VERSION 5.8 ;
BUSBITCHARS "[]" ;
DIVIDERCHAR "/" ;
UNITS
    DATABASE MICRONS 1000 ;
END UNITS

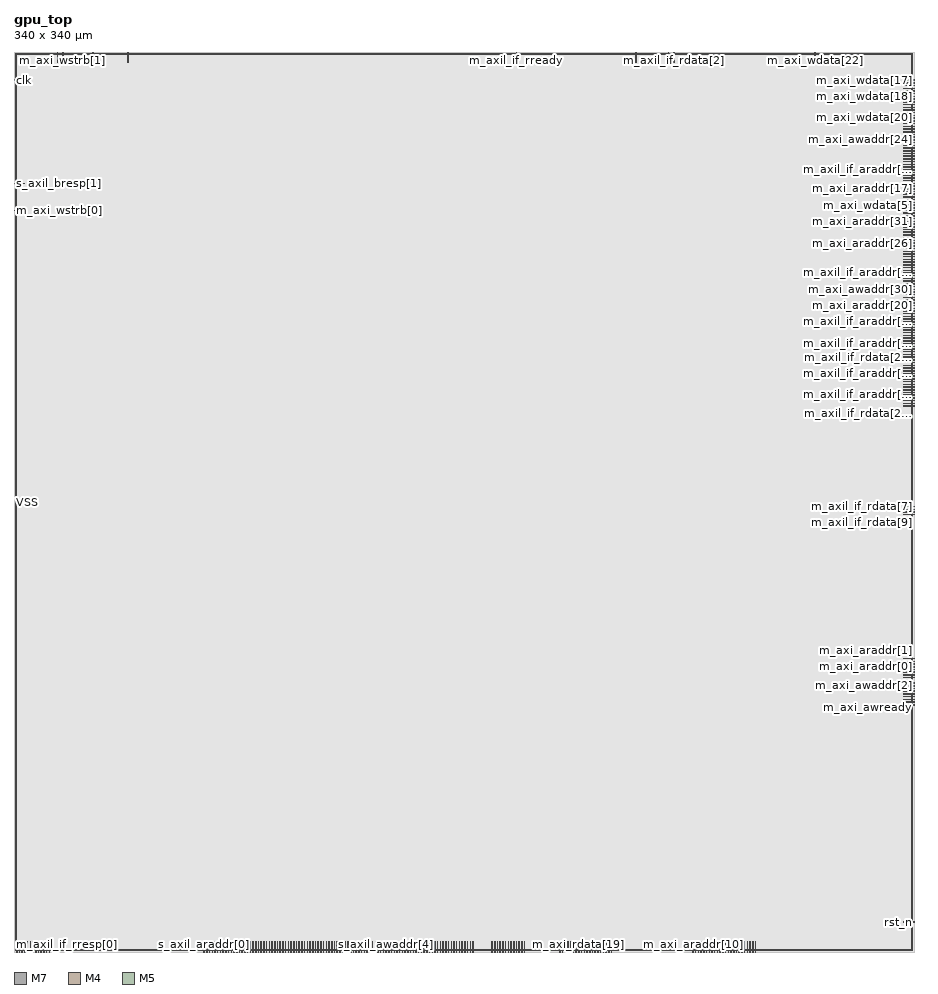
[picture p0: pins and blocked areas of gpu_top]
MACRO gpu_top
  FOREIGN gpu_top 0 0 ;
  CLASS BLOCK ;
  SIZE 340 BY 340 ;
  PIN VDD
    USE POWER ;
    DIRECTION INOUT ;
    PORT
      LAYER M7 ;
        RECT 0.500 0.500 339.500 0.660 ;
        RECT 0.500 339.340 339.500 339.500 ;
        RECT 0.500 0.500 0.660 339.500 ;
        RECT 339.340 0.500 339.500 339.500 ;
    END
  END VDD
  PIN VSS
    USE GROUND ;
    DIRECTION INOUT ;
    PORT
      LAYER M7 ;
        RECT 0.500 0.820 339.500 0.980 ;
        RECT 0.500 339.020 339.500 339.180 ;
        RECT 0.500 0.820 0.980 339.180 ;
        RECT 339.020 0.500 339.180 339.500 ;
    END
  END VSS
  PIN clk
    DIRECTION INPUT ;
    USE SIGNAL ;
    PORT
      LAYER M4 ;
        RECT  0 329.268 4 329.46 ;
    END
  END clk
  PIN gpu_irq_o
    DIRECTION OUTPUT ;
    USE SIGNAL ;
    PORT
      LAYER M5 ;
        RECT  116.886 0 117.078 4 ;
    END
  END gpu_irq_o
  PIN m_axi_araddr[0]
    DIRECTION OUTPUT ;
    USE SIGNAL ;
    PORT
      LAYER M4 ;
        RECT  336 107.652 340 107.844 ;
    END
  END m_axi_araddr[0]
  PIN m_axi_araddr[10]
    DIRECTION OUTPUT ;
    USE SIGNAL ;
    PORT
      LAYER M5 ;
        RECT  256.422 0 256.614 4 ;
    END
  END m_axi_araddr[10]
  PIN m_axi_araddr[11]
    DIRECTION OUTPUT ;
    USE SIGNAL ;
    PORT
      LAYER M5 ;
        RECT  258.474 0 258.666 4 ;
    END
  END m_axi_araddr[11]
  PIN m_axi_araddr[12]
    DIRECTION OUTPUT ;
    USE SIGNAL ;
    PORT
      LAYER M5 ;
        RECT  266.682 0 266.874 4 ;
    END
  END m_axi_araddr[12]
  PIN m_axi_araddr[13]
    DIRECTION OUTPUT ;
    USE SIGNAL ;
    PORT
      LAYER M5 ;
        RECT  260.526 0 260.718 4 ;
    END
  END m_axi_araddr[13]
  PIN m_axi_araddr[14]
    DIRECTION OUTPUT ;
    USE SIGNAL ;
    PORT
      LAYER M5 ;
        RECT  280.02 0 280.212 4 ;
    END
  END m_axi_araddr[14]
  PIN m_axi_araddr[15]
    DIRECTION OUTPUT ;
    USE SIGNAL ;
    PORT
      LAYER M5 ;
        RECT  269.76 0 269.952 4 ;
    END
  END m_axi_araddr[15]
  PIN m_axi_araddr[16]
    DIRECTION OUTPUT ;
    USE SIGNAL ;
    PORT
      LAYER M4 ;
        RECT  336 314.904 340 315.096 ;
    END
  END m_axi_araddr[16]
  PIN m_axi_araddr[17]
    DIRECTION OUTPUT ;
    USE SIGNAL ;
    PORT
      LAYER M4 ;
        RECT  336 291.306 340 291.498 ;
    END
  END m_axi_araddr[17]
  PIN m_axi_araddr[18]
    DIRECTION OUTPUT ;
    USE SIGNAL ;
    PORT
      LAYER M4 ;
        RECT  336 273.864 340 274.056 ;
    END
  END m_axi_araddr[18]
  PIN m_axi_araddr[19]
    DIRECTION OUTPUT ;
    USE SIGNAL ;
    PORT
      LAYER M4 ;
        RECT  336 274.89 340 275.082 ;
    END
  END m_axi_araddr[19]
  PIN m_axi_araddr[1]
    DIRECTION OUTPUT ;
    USE SIGNAL ;
    PORT
      LAYER M4 ;
        RECT  336 110.73 340 110.922 ;
    END
  END m_axi_araddr[1]
  PIN m_axi_araddr[20]
    DIRECTION OUTPUT ;
    USE SIGNAL ;
    PORT
      LAYER M4 ;
        RECT  336 244.11 340 244.302 ;
    END
  END m_axi_araddr[20]
  PIN m_axi_araddr[21]
    DIRECTION OUTPUT ;
    USE SIGNAL ;
    PORT
      LAYER M4 ;
        RECT  336 290.28 340 290.472 ;
    END
  END m_axi_araddr[21]
  PIN m_axi_araddr[22]
    DIRECTION OUTPUT ;
    USE SIGNAL ;
    PORT
      LAYER M4 ;
        RECT  336 258.474 340 258.666 ;
    END
  END m_axi_araddr[22]
  PIN m_axi_araddr[23]
    DIRECTION OUTPUT ;
    USE SIGNAL ;
    PORT
      LAYER M4 ;
        RECT  336 312.852 340 313.044 ;
    END
  END m_axi_araddr[23]
  PIN m_axi_araddr[24]
    DIRECTION OUTPUT ;
    USE SIGNAL ;
    PORT
      LAYER M4 ;
        RECT  336 251.292 340 251.484 ;
    END
  END m_axi_araddr[24]
  PIN m_axi_araddr[25]
    DIRECTION OUTPUT ;
    USE SIGNAL ;
    PORT
      LAYER M4 ;
        RECT  336 263.604 340 263.796 ;
    END
  END m_axi_araddr[25]
  PIN m_axi_araddr[26]
    DIRECTION OUTPUT ;
    USE SIGNAL ;
    PORT
      LAYER M4 ;
        RECT  336 267.708 340 267.9 ;
    END
  END m_axi_araddr[26]
  PIN m_axi_araddr[27]
    DIRECTION OUTPUT ;
    USE SIGNAL ;
    PORT
      LAYER M4 ;
        RECT  336 303.618 340 303.81 ;
    END
  END m_axi_araddr[27]
  PIN m_axi_araddr[28]
    DIRECTION OUTPUT ;
    USE SIGNAL ;
    PORT
      LAYER M4 ;
        RECT  336 277.968 340 278.16 ;
    END
  END m_axi_araddr[28]
  PIN m_axi_araddr[29]
    DIRECTION OUTPUT ;
    USE SIGNAL ;
    PORT
      LAYER M4 ;
        RECT  336 245.136 340 245.328 ;
    END
  END m_axi_araddr[29]
  PIN m_axi_araddr[2]
    DIRECTION OUTPUT ;
    USE SIGNAL ;
    PORT
      LAYER M4 ;
        RECT  336 104.574 340 104.766 ;
    END
  END m_axi_araddr[2]
  PIN m_axi_araddr[30]
    DIRECTION OUTPUT ;
    USE SIGNAL ;
    PORT
      LAYER M4 ;
        RECT  336 310.8 340 310.992 ;
    END
  END m_axi_araddr[30]
  PIN m_axi_araddr[31]
    DIRECTION OUTPUT ;
    USE SIGNAL ;
    PORT
      LAYER M4 ;
        RECT  336 272.838 340 273.03 ;
    END
  END m_axi_araddr[31]
  PIN m_axi_araddr[3]
    DIRECTION OUTPUT ;
    USE SIGNAL ;
    PORT
      LAYER M4 ;
        RECT  336 105.6 340 105.792 ;
    END
  END m_axi_araddr[3]
  PIN m_axi_araddr[4]
    DIRECTION OUTPUT ;
    USE SIGNAL ;
    PORT
      LAYER M5 ;
        RECT  267.708 0 267.9 4 ;
    END
  END m_axi_araddr[4]
  PIN m_axi_araddr[5]
    DIRECTION OUTPUT ;
    USE SIGNAL ;
    PORT
      LAYER M5 ;
        RECT  278.994 0 279.186 4 ;
    END
  END m_axi_araddr[5]
  PIN m_axi_araddr[6]
    DIRECTION OUTPUT ;
    USE SIGNAL ;
    PORT
      LAYER M5 ;
        RECT  263.604 0 263.796 4 ;
    END
  END m_axi_araddr[6]
  PIN m_axi_araddr[7]
    DIRECTION OUTPUT ;
    USE SIGNAL ;
    PORT
      LAYER M5 ;
        RECT  257.448 0 257.64 4 ;
    END
  END m_axi_araddr[7]
  PIN m_axi_araddr[8]
    DIRECTION OUTPUT ;
    USE SIGNAL ;
    PORT
      LAYER M5 ;
        RECT  272.838 0 273.03 4 ;
    END
  END m_axi_araddr[8]
  PIN m_axi_araddr[9]
    DIRECTION OUTPUT ;
    USE SIGNAL ;
    PORT
      LAYER M5 ;
        RECT  277.968 0 278.16 4 ;
    END
  END m_axi_araddr[9]
  PIN m_axi_arready
    DIRECTION INPUT ;
    USE SIGNAL ;
    PORT
      LAYER M4 ;
        RECT  336 93.288 340 93.48 ;
    END
  END m_axi_arready
  PIN m_axi_arvalid
    DIRECTION OUTPUT ;
    USE SIGNAL ;
    PORT
      LAYER M4 ;
        RECT  336 94.314 340 94.506 ;
    END
  END m_axi_arvalid
  PIN m_axi_awaddr[0]
    DIRECTION OUTPUT ;
    USE SIGNAL ;
    PORT
      LAYER M4 ;
        RECT  336 108.678 340 108.87 ;
    END
  END m_axi_awaddr[0]
  PIN m_axi_awaddr[10]
    DIRECTION OUTPUT ;
    USE SIGNAL ;
    PORT
      LAYER M5 ;
        RECT  265.656 0 265.848 4 ;
    END
  END m_axi_awaddr[10]
  PIN m_axi_awaddr[11]
    DIRECTION OUTPUT ;
    USE SIGNAL ;
    PORT
      LAYER M5 ;
        RECT  268.734 0 268.926 4 ;
    END
  END m_axi_awaddr[11]
  PIN m_axi_awaddr[12]
    DIRECTION OUTPUT ;
    USE SIGNAL ;
    PORT
      LAYER M5 ;
        RECT  264.63 0 264.822 4 ;
    END
  END m_axi_awaddr[12]
  PIN m_axi_awaddr[13]
    DIRECTION OUTPUT ;
    USE SIGNAL ;
    PORT
      LAYER M5 ;
        RECT  259.5 0 259.692 4 ;
    END
  END m_axi_awaddr[13]
  PIN m_axi_awaddr[14]
    DIRECTION OUTPUT ;
    USE SIGNAL ;
    PORT
      LAYER M5 ;
        RECT  270.786 0 270.978 4 ;
    END
  END m_axi_awaddr[14]
  PIN m_axi_awaddr[15]
    DIRECTION OUTPUT ;
    USE SIGNAL ;
    PORT
      LAYER M5 ;
        RECT  275.916 0 276.108 4 ;
    END
  END m_axi_awaddr[15]
  PIN m_axi_awaddr[16]
    DIRECTION OUTPUT ;
    USE SIGNAL ;
    PORT
      LAYER M4 ;
        RECT  336 288.228 340 288.42 ;
    END
  END m_axi_awaddr[16]
  PIN m_axi_awaddr[17]
    DIRECTION OUTPUT ;
    USE SIGNAL ;
    PORT
      LAYER M4 ;
        RECT  336 305.67 340 305.862 ;
    END
  END m_axi_awaddr[17]
  PIN m_axi_awaddr[18]
    DIRECTION OUTPUT ;
    USE SIGNAL ;
    PORT
      LAYER M4 ;
        RECT  336 252.318 340 252.51 ;
    END
  END m_axi_awaddr[18]
  PIN m_axi_awaddr[19]
    DIRECTION OUTPUT ;
    USE SIGNAL ;
    PORT
      LAYER M4 ;
        RECT  336 292.332 340 292.524 ;
    END
  END m_axi_awaddr[19]
  PIN m_axi_awaddr[1]
    DIRECTION OUTPUT ;
    USE SIGNAL ;
    PORT
      LAYER M4 ;
        RECT  336 109.704 340 109.896 ;
    END
  END m_axi_awaddr[1]
  PIN m_axi_awaddr[20]
    DIRECTION OUTPUT ;
    USE SIGNAL ;
    PORT
      LAYER M4 ;
        RECT  336 243.084 340 243.276 ;
    END
  END m_axi_awaddr[20]
  PIN m_axi_awaddr[21]
    DIRECTION OUTPUT ;
    USE SIGNAL ;
    PORT
      LAYER M4 ;
        RECT  336 293.358 340 293.55 ;
    END
  END m_axi_awaddr[21]
  PIN m_axi_awaddr[22]
    DIRECTION OUTPUT ;
    USE SIGNAL ;
    PORT
      LAYER M4 ;
        RECT  336 280.02 340 280.212 ;
    END
  END m_axi_awaddr[22]
  PIN m_axi_awaddr[23]
    DIRECTION OUTPUT ;
    USE SIGNAL ;
    PORT
      LAYER M4 ;
        RECT  336 255.396 340 255.588 ;
    END
  END m_axi_awaddr[23]
  PIN m_axi_awaddr[24]
    DIRECTION OUTPUT ;
    USE SIGNAL ;
    PORT
      LAYER M4 ;
        RECT  336 306.696 340 306.888 ;
    END
  END m_axi_awaddr[24]
  PIN m_axi_awaddr[25]
    DIRECTION OUTPUT ;
    USE SIGNAL ;
    PORT
      LAYER M4 ;
        RECT  336 302.592 340 302.784 ;
    END
  END m_axi_awaddr[25]
  PIN m_axi_awaddr[26]
    DIRECTION OUTPUT ;
    USE SIGNAL ;
    PORT
      LAYER M4 ;
        RECT  336 297.462 340 297.654 ;
    END
  END m_axi_awaddr[26]
  PIN m_axi_awaddr[27]
    DIRECTION OUTPUT ;
    USE SIGNAL ;
    PORT
      LAYER M4 ;
        RECT  336 282.072 340 282.264 ;
    END
  END m_axi_awaddr[27]
  PIN m_axi_awaddr[28]
    DIRECTION OUTPUT ;
    USE SIGNAL ;
    PORT
      LAYER M4 ;
        RECT  336 276.942 340 277.134 ;
    END
  END m_axi_awaddr[28]
  PIN m_axi_awaddr[29]
    DIRECTION OUTPUT ;
    USE SIGNAL ;
    PORT
      LAYER M4 ;
        RECT  336 246.162 340 246.354 ;
    END
  END m_axi_awaddr[29]
  PIN m_axi_awaddr[2]
    DIRECTION OUTPUT ;
    USE SIGNAL ;
    PORT
      LAYER M4 ;
        RECT  336 103.548 340 103.74 ;
    END
  END m_axi_awaddr[2]
  PIN m_axi_awaddr[30]
    DIRECTION OUTPUT ;
    USE SIGNAL ;
    PORT
      LAYER M4 ;
        RECT  336 247.188 340 247.38 ;
    END
  END m_axi_awaddr[30]
  PIN m_axi_awaddr[31]
    DIRECTION OUTPUT ;
    USE SIGNAL ;
    PORT
      LAYER M4 ;
        RECT  336 271.812 340 272.004 ;
    END
  END m_axi_awaddr[31]
  PIN m_axi_awaddr[3]
    DIRECTION OUTPUT ;
    USE SIGNAL ;
    PORT
      LAYER M4 ;
        RECT  336 106.626 340 106.818 ;
    END
  END m_axi_awaddr[3]
  PIN m_axi_awaddr[4]
    DIRECTION OUTPUT ;
    USE SIGNAL ;
    PORT
      LAYER M5 ;
        RECT  262.578 0 262.77 4 ;
    END
  END m_axi_awaddr[4]
  PIN m_axi_awaddr[5]
    DIRECTION OUTPUT ;
    USE SIGNAL ;
    PORT
      LAYER M5 ;
        RECT  276.942 0 277.134 4 ;
    END
  END m_axi_awaddr[5]
  PIN m_axi_awaddr[6]
    DIRECTION OUTPUT ;
    USE SIGNAL ;
    PORT
      LAYER M5 ;
        RECT  261.552 0 261.744 4 ;
    END
  END m_axi_awaddr[6]
  PIN m_axi_awaddr[7]
    DIRECTION OUTPUT ;
    USE SIGNAL ;
    PORT
      LAYER M5 ;
        RECT  274.89 0 275.082 4 ;
    END
  END m_axi_awaddr[7]
  PIN m_axi_awaddr[8]
    DIRECTION OUTPUT ;
    USE SIGNAL ;
    PORT
      LAYER M5 ;
        RECT  273.864 0 274.056 4 ;
    END
  END m_axi_awaddr[8]
  PIN m_axi_awaddr[9]
    DIRECTION OUTPUT ;
    USE SIGNAL ;
    PORT
      LAYER M5 ;
        RECT  271.812 0 272.004 4 ;
    END
  END m_axi_awaddr[9]
  PIN m_axi_awready
    DIRECTION INPUT ;
    USE SIGNAL ;
    PORT
      LAYER M4 ;
        RECT  336 95.34 340 95.532 ;
    END
  END m_axi_awready
  PIN m_axi_awvalid
    DIRECTION OUTPUT ;
    USE SIGNAL ;
    PORT
      LAYER M4 ;
        RECT  336 96.366 340 96.558 ;
    END
  END m_axi_awvalid
  PIN m_axi_bready
    DIRECTION OUTPUT ;
    USE SIGNAL ;
    PORT
      LAYER M4 ;
        RECT  336 101.496 340 101.688 ;
    END
  END m_axi_bready
  PIN m_axi_bresp[0]
    DIRECTION INPUT ;
    USE SIGNAL ;
    PORT
      LAYER M5 ;
        RECT  0.948 0 1.14 4 ;
    END
  END m_axi_bresp[0]
  PIN m_axi_bresp[1]
    DIRECTION INPUT ;
    USE SIGNAL ;
    PORT
      LAYER M5 ;
        RECT  1.974 0 2.166 4 ;
    END
  END m_axi_bresp[1]
  PIN m_axi_bvalid
    DIRECTION INPUT ;
    USE SIGNAL ;
    PORT
      LAYER M4 ;
        RECT  336 100.47 340 100.662 ;
    END
  END m_axi_bvalid
  PIN m_axi_rdata[0]
    DIRECTION INPUT ;
    USE SIGNAL ;
    PORT
      LAYER M5 ;
        RECT  225.642 0 225.834 4 ;
    END
  END m_axi_rdata[0]
  PIN m_axi_rdata[10]
    DIRECTION INPUT ;
    USE SIGNAL ;
    PORT
      LAYER M5 ;
        RECT  180.498 0 180.69 4 ;
    END
  END m_axi_rdata[10]
  PIN m_axi_rdata[11]
    DIRECTION INPUT ;
    USE SIGNAL ;
    PORT
      LAYER M5 ;
        RECT  192.81 0 193.002 4 ;
    END
  END m_axi_rdata[11]
  PIN m_axi_rdata[12]
    DIRECTION INPUT ;
    USE SIGNAL ;
    PORT
      LAYER M5 ;
        RECT  188.706 0 188.898 4 ;
    END
  END m_axi_rdata[12]
  PIN m_axi_rdata[13]
    DIRECTION INPUT ;
    USE SIGNAL ;
    PORT
      LAYER M5 ;
        RECT  181.524 0 181.716 4 ;
    END
  END m_axi_rdata[13]
  PIN m_axi_rdata[14]
    DIRECTION INPUT ;
    USE SIGNAL ;
    PORT
      LAYER M5 ;
        RECT  191.784 0 191.976 4 ;
    END
  END m_axi_rdata[14]
  PIN m_axi_rdata[15]
    DIRECTION INPUT ;
    USE SIGNAL ;
    PORT
      LAYER M5 ;
        RECT  215.382 0 215.574 4 ;
    END
  END m_axi_rdata[15]
  PIN m_axi_rdata[16]
    DIRECTION INPUT ;
    USE SIGNAL ;
    PORT
      LAYER M5 ;
        RECT  222.564 0 222.756 4 ;
    END
  END m_axi_rdata[16]
  PIN m_axi_rdata[17]
    DIRECTION INPUT ;
    USE SIGNAL ;
    PORT
      LAYER M5 ;
        RECT  207.174 0 207.366 4 ;
    END
  END m_axi_rdata[17]
  PIN m_axi_rdata[18]
    DIRECTION INPUT ;
    USE SIGNAL ;
    PORT
      LAYER M5 ;
        RECT  216.408 0 216.6 4 ;
    END
  END m_axi_rdata[18]
  PIN m_axi_rdata[19]
    DIRECTION INPUT ;
    USE SIGNAL ;
    PORT
      LAYER M5 ;
        RECT  213.33 0 213.522 4 ;
    END
  END m_axi_rdata[19]
  PIN m_axi_rdata[1]
    DIRECTION INPUT ;
    USE SIGNAL ;
    PORT
      LAYER M5 ;
        RECT  223.59 0 223.782 4 ;
    END
  END m_axi_rdata[1]
  PIN m_axi_rdata[20]
    DIRECTION INPUT ;
    USE SIGNAL ;
    PORT
      LAYER M5 ;
        RECT  209.226 0 209.418 4 ;
    END
  END m_axi_rdata[20]
  PIN m_axi_rdata[21]
    DIRECTION INPUT ;
    USE SIGNAL ;
    PORT
      LAYER M5 ;
        RECT  224.616 0 224.808 4 ;
    END
  END m_axi_rdata[21]
  PIN m_axi_rdata[22]
    DIRECTION INPUT ;
    USE SIGNAL ;
    PORT
      LAYER M5 ;
        RECT  210.252 0 210.444 4 ;
    END
  END m_axi_rdata[22]
  PIN m_axi_rdata[23]
    DIRECTION INPUT ;
    USE SIGNAL ;
    PORT
      LAYER M5 ;
        RECT  211.278 0 211.47 4 ;
    END
  END m_axi_rdata[23]
  PIN m_axi_rdata[24]
    DIRECTION INPUT ;
    USE SIGNAL ;
    PORT
      LAYER M5 ;
        RECT  219.486 0 219.678 4 ;
    END
  END m_axi_rdata[24]
  PIN m_axi_rdata[25]
    DIRECTION INPUT ;
    USE SIGNAL ;
    PORT
      LAYER M5 ;
        RECT  212.304 0 212.496 4 ;
    END
  END m_axi_rdata[25]
  PIN m_axi_rdata[26]
    DIRECTION INPUT ;
    USE SIGNAL ;
    PORT
      LAYER M5 ;
        RECT  214.356 0 214.548 4 ;
    END
  END m_axi_rdata[26]
  PIN m_axi_rdata[27]
    DIRECTION INPUT ;
    USE SIGNAL ;
    PORT
      LAYER M5 ;
        RECT  220.512 0 220.704 4 ;
    END
  END m_axi_rdata[27]
  PIN m_axi_rdata[28]
    DIRECTION INPUT ;
    USE SIGNAL ;
    PORT
      LAYER M5 ;
        RECT  208.2 0 208.392 4 ;
    END
  END m_axi_rdata[28]
  PIN m_axi_rdata[29]
    DIRECTION INPUT ;
    USE SIGNAL ;
    PORT
      LAYER M5 ;
        RECT  206.148 0 206.34 4 ;
    END
  END m_axi_rdata[29]
  PIN m_axi_rdata[2]
    DIRECTION INPUT ;
    USE SIGNAL ;
    PORT
      LAYER M5 ;
        RECT  189.732 0 189.924 4 ;
    END
  END m_axi_rdata[2]
  PIN m_axi_rdata[30]
    DIRECTION INPUT ;
    USE SIGNAL ;
    PORT
      LAYER M5 ;
        RECT  217.434 0 217.626 4 ;
    END
  END m_axi_rdata[30]
  PIN m_axi_rdata[31]
    DIRECTION INPUT ;
    USE SIGNAL ;
    PORT
      LAYER M5 ;
        RECT  221.538 0 221.73 4 ;
    END
  END m_axi_rdata[31]
  PIN m_axi_rdata[3]
    DIRECTION INPUT ;
    USE SIGNAL ;
    PORT
      LAYER M5 ;
        RECT  187.68 0 187.872 4 ;
    END
  END m_axi_rdata[3]
  PIN m_axi_rdata[4]
    DIRECTION INPUT ;
    USE SIGNAL ;
    PORT
      LAYER M5 ;
        RECT  184.602 0 184.794 4 ;
    END
  END m_axi_rdata[4]
  PIN m_axi_rdata[5]
    DIRECTION INPUT ;
    USE SIGNAL ;
    PORT
      LAYER M5 ;
        RECT  183.576 0 183.768 4 ;
    END
  END m_axi_rdata[5]
  PIN m_axi_rdata[6]
    DIRECTION INPUT ;
    USE SIGNAL ;
    PORT
      LAYER M5 ;
        RECT  190.758 0 190.95 4 ;
    END
  END m_axi_rdata[6]
  PIN m_axi_rdata[7]
    DIRECTION INPUT ;
    USE SIGNAL ;
    PORT
      LAYER M5 ;
        RECT  182.55 0 182.742 4 ;
    END
  END m_axi_rdata[7]
  PIN m_axi_rdata[8]
    DIRECTION INPUT ;
    USE SIGNAL ;
    PORT
      LAYER M5 ;
        RECT  185.628 0 185.82 4 ;
    END
  END m_axi_rdata[8]
  PIN m_axi_rdata[9]
    DIRECTION INPUT ;
    USE SIGNAL ;
    PORT
      LAYER M5 ;
        RECT  186.654 0 186.846 4 ;
    END
  END m_axi_rdata[9]
  PIN m_axi_rready
    DIRECTION OUTPUT ;
    USE SIGNAL ;
    PORT
      LAYER M4 ;
        RECT  336 99.444 340 99.636 ;
    END
  END m_axi_rready
  PIN m_axi_rresp[0]
    DIRECTION INPUT ;
    USE SIGNAL ;
    PORT
      LAYER M5 ;
        RECT  3 0 3.192 4 ;
    END
  END m_axi_rresp[0]
  PIN m_axi_rresp[1]
    DIRECTION INPUT ;
    USE SIGNAL ;
    PORT
      LAYER M5 ;
        RECT  4.026 0 4.218 4 ;
    END
  END m_axi_rresp[1]
  PIN m_axi_rvalid
    DIRECTION INPUT ;
    USE SIGNAL ;
    PORT
      LAYER M5 ;
        RECT  218.46 0 218.652 4 ;
    END
  END m_axi_rvalid
  PIN m_axi_wdata[0]
    DIRECTION OUTPUT ;
    USE SIGNAL ;
    PORT
      LAYER M4 ;
        RECT  336 268.734 340 268.926 ;
    END
  END m_axi_wdata[0]
  PIN m_axi_wdata[10]
    DIRECTION OUTPUT ;
    USE SIGNAL ;
    PORT
      LAYER M4 ;
        RECT  336 270.786 340 270.978 ;
    END
  END m_axi_wdata[10]
  PIN m_axi_wdata[11]
    DIRECTION OUTPUT ;
    USE SIGNAL ;
    PORT
      LAYER M4 ;
        RECT  336 275.916 340 276.108 ;
    END
  END m_axi_wdata[11]
  PIN m_axi_wdata[12]
    DIRECTION OUTPUT ;
    USE SIGNAL ;
    PORT
      LAYER M4 ;
        RECT  336 285.15 340 285.342 ;
    END
  END m_axi_wdata[12]
  PIN m_axi_wdata[13]
    DIRECTION OUTPUT ;
    USE SIGNAL ;
    PORT
      LAYER M4 ;
        RECT  336 313.878 340 314.07 ;
    END
  END m_axi_wdata[13]
  PIN m_axi_wdata[14]
    DIRECTION OUTPUT ;
    USE SIGNAL ;
    PORT
      LAYER M4 ;
        RECT  336 261.552 340 261.744 ;
    END
  END m_axi_wdata[14]
  PIN m_axi_wdata[15]
    DIRECTION OUTPUT ;
    USE SIGNAL ;
    PORT
      LAYER M4 ;
        RECT  336 307.722 340 307.914 ;
    END
  END m_axi_wdata[15]
  PIN m_axi_wdata[16]
    DIRECTION OUTPUT ;
    USE SIGNAL ;
    PORT
      LAYER M4 ;
        RECT  336 315.93 340 316.122 ;
    END
  END m_axi_wdata[16]
  PIN m_axi_wdata[17]
    DIRECTION OUTPUT ;
    USE SIGNAL ;
    PORT
      LAYER M4 ;
        RECT  336 329.268 340 329.46 ;
    END
  END m_axi_wdata[17]
  PIN m_axi_wdata[18]
    DIRECTION OUTPUT ;
    USE SIGNAL ;
    PORT
      LAYER M4 ;
        RECT  336 323.112 340 323.304 ;
    END
  END m_axi_wdata[18]
  PIN m_axi_wdata[19]
    DIRECTION OUTPUT ;
    USE SIGNAL ;
    PORT
      LAYER M4 ;
        RECT  336 319.008 340 319.2 ;
    END
  END m_axi_wdata[19]
  PIN m_axi_wdata[1]
    DIRECTION OUTPUT ;
    USE SIGNAL ;
    PORT
      LAYER M4 ;
        RECT  336 304.644 340 304.836 ;
    END
  END m_axi_wdata[1]
  PIN m_axi_wdata[20]
    DIRECTION OUTPUT ;
    USE SIGNAL ;
    PORT
      LAYER M4 ;
        RECT  336 317.982 340 318.174 ;
    END
  END m_axi_wdata[20]
  PIN m_axi_wdata[21]
    DIRECTION OUTPUT ;
    USE SIGNAL ;
    PORT
      LAYER M4 ;
        RECT  336 311.826 340 312.018 ;
    END
  END m_axi_wdata[21]
  PIN m_axi_wdata[22]
    DIRECTION OUTPUT ;
    USE SIGNAL ;
    PORT
      LAYER M5 ;
        RECT  302.592 336 302.784 340 ;
    END
  END m_axi_wdata[22]
  PIN m_axi_wdata[23]
    DIRECTION OUTPUT ;
    USE SIGNAL ;
    PORT
      LAYER M4 ;
        RECT  336 316.956 340 317.148 ;
    END
  END m_axi_wdata[23]
  PIN m_axi_wdata[24]
    DIRECTION OUTPUT ;
    USE SIGNAL ;
    PORT
      LAYER M4 ;
        RECT  336 328.242 340 328.434 ;
    END
  END m_axi_wdata[24]
  PIN m_axi_wdata[25]
    DIRECTION OUTPUT ;
    USE SIGNAL ;
    PORT
      LAYER M4 ;
        RECT  336 320.034 340 320.226 ;
    END
  END m_axi_wdata[25]
  PIN m_axi_wdata[26]
    DIRECTION OUTPUT ;
    USE SIGNAL ;
    PORT
      LAYER M4 ;
        RECT  336 326.19 340 326.382 ;
    END
  END m_axi_wdata[26]
  PIN m_axi_wdata[27]
    DIRECTION OUTPUT ;
    USE SIGNAL ;
    PORT
      LAYER M4 ;
        RECT  336 322.086 340 322.278 ;
    END
  END m_axi_wdata[27]
  PIN m_axi_wdata[28]
    DIRECTION OUTPUT ;
    USE SIGNAL ;
    PORT
      LAYER M4 ;
        RECT  336 298.488 340 298.68 ;
    END
  END m_axi_wdata[28]
  PIN m_axi_wdata[29]
    DIRECTION OUTPUT ;
    USE SIGNAL ;
    PORT
      LAYER M4 ;
        RECT  336 325.164 340 325.356 ;
    END
  END m_axi_wdata[29]
  PIN m_axi_wdata[2]
    DIRECTION OUTPUT ;
    USE SIGNAL ;
    PORT
      LAYER M4 ;
        RECT  336 264.63 340 264.822 ;
    END
  END m_axi_wdata[2]
  PIN m_axi_wdata[30]
    DIRECTION OUTPUT ;
    USE SIGNAL ;
    PORT
      LAYER M4 ;
        RECT  336 324.138 340 324.33 ;
    END
  END m_axi_wdata[30]
  PIN m_axi_wdata[31]
    DIRECTION OUTPUT ;
    USE SIGNAL ;
    PORT
      LAYER M4 ;
        RECT  336 321.06 340 321.252 ;
    END
  END m_axi_wdata[31]
  PIN m_axi_wdata[3]
    DIRECTION OUTPUT ;
    USE SIGNAL ;
    PORT
      LAYER M4 ;
        RECT  336 283.098 340 283.29 ;
    END
  END m_axi_wdata[3]
  PIN m_axi_wdata[4]
    DIRECTION OUTPUT ;
    USE SIGNAL ;
    PORT
      LAYER M4 ;
        RECT  336 289.254 340 289.446 ;
    END
  END m_axi_wdata[4]
  PIN m_axi_wdata[5]
    DIRECTION OUTPUT ;
    USE SIGNAL ;
    PORT
      LAYER M4 ;
        RECT  336 278.994 340 279.186 ;
    END
  END m_axi_wdata[5]
  PIN m_axi_wdata[6]
    DIRECTION OUTPUT ;
    USE SIGNAL ;
    PORT
      LAYER M4 ;
        RECT  336 269.76 340 269.952 ;
    END
  END m_axi_wdata[6]
  PIN m_axi_wdata[7]
    DIRECTION OUTPUT ;
    USE SIGNAL ;
    PORT
      LAYER M4 ;
        RECT  336 257.448 340 257.64 ;
    END
  END m_axi_wdata[7]
  PIN m_axi_wdata[8]
    DIRECTION OUTPUT ;
    USE SIGNAL ;
    PORT
      LAYER M4 ;
        RECT  336 254.37 340 254.562 ;
    END
  END m_axi_wdata[8]
  PIN m_axi_wdata[9]
    DIRECTION OUTPUT ;
    USE SIGNAL ;
    PORT
      LAYER M4 ;
        RECT  336 260.526 340 260.718 ;
    END
  END m_axi_wdata[9]
  PIN m_axi_wready
    DIRECTION INPUT ;
    USE SIGNAL ;
    PORT
      LAYER M4 ;
        RECT  336 98.418 340 98.61 ;
    END
  END m_axi_wready
  PIN m_axi_wstrb[0]
    DIRECTION OUTPUT ;
    USE SIGNAL ;
    PORT
      LAYER M4 ;
        RECT  0 280.02 4 280.212 ;
    END
  END m_axi_wstrb[0]
  PIN m_axi_wstrb[1]
    DIRECTION OUTPUT ;
    USE SIGNAL ;
    PORT
      LAYER M5 ;
        RECT  18.39 336 18.582 340 ;
    END
  END m_axi_wstrb[1]
  PIN m_axi_wstrb[2]
    DIRECTION OUTPUT ;
    USE SIGNAL ;
    PORT
      LAYER M4 ;
        RECT  336 327.216 340 327.408 ;
    END
  END m_axi_wstrb[2]
  PIN m_axi_wstrb[3]
    DIRECTION OUTPUT ;
    USE SIGNAL ;
    PORT
      LAYER M5 ;
        RECT  16.338 336 16.53 340 ;
    END
  END m_axi_wstrb[3]
  PIN m_axi_wvalid
    DIRECTION OUTPUT ;
    USE SIGNAL ;
    PORT
      LAYER M4 ;
        RECT  336 97.392 340 97.584 ;
    END
  END m_axi_wvalid
  PIN m_axil_if_araddr[0]
    DIRECTION OUTPUT ;
    USE SIGNAL ;
    PORT
      LAYER M4 ;
        RECT  336 241.032 340 241.224 ;
    END
  END m_axil_if_araddr[0]
  PIN m_axil_if_araddr[10]
    DIRECTION OUTPUT ;
    USE SIGNAL ;
    PORT
      LAYER M4 ;
        RECT  336 222.564 340 222.756 ;
    END
  END m_axil_if_araddr[10]
  PIN m_axil_if_araddr[11]
    DIRECTION OUTPUT ;
    USE SIGNAL ;
    PORT
      LAYER M4 ;
        RECT  336 214.356 340 214.548 ;
    END
  END m_axil_if_araddr[11]
  PIN m_axil_if_araddr[12]
    DIRECTION OUTPUT ;
    USE SIGNAL ;
    PORT
      LAYER M4 ;
        RECT  336 227.694 340 227.886 ;
    END
  END m_axil_if_araddr[12]
  PIN m_axil_if_araddr[13]
    DIRECTION OUTPUT ;
    USE SIGNAL ;
    PORT
      LAYER M4 ;
        RECT  336 218.46 340 218.652 ;
    END
  END m_axil_if_araddr[13]
  PIN m_axil_if_araddr[14]
    DIRECTION OUTPUT ;
    USE SIGNAL ;
    PORT
      LAYER M4 ;
        RECT  336 223.59 340 223.782 ;
    END
  END m_axil_if_araddr[14]
  PIN m_axil_if_araddr[15]
    DIRECTION OUTPUT ;
    USE SIGNAL ;
    PORT
      LAYER M4 ;
        RECT  336 213.33 340 213.522 ;
    END
  END m_axil_if_araddr[15]
  PIN m_axil_if_araddr[16]
    DIRECTION OUTPUT ;
    USE SIGNAL ;
    PORT
      LAYER M4 ;
        RECT  336 238.98 340 239.172 ;
    END
  END m_axil_if_araddr[16]
  PIN m_axil_if_araddr[17]
    DIRECTION OUTPUT ;
    USE SIGNAL ;
    PORT
      LAYER M4 ;
        RECT  336 216.408 340 216.6 ;
    END
  END m_axil_if_araddr[17]
  PIN m_axil_if_araddr[18]
    DIRECTION OUTPUT ;
    USE SIGNAL ;
    PORT
      LAYER M4 ;
        RECT  336 233.85 340 234.042 ;
    END
  END m_axil_if_araddr[18]
  PIN m_axil_if_araddr[19]
    DIRECTION OUTPUT ;
    USE SIGNAL ;
    PORT
      LAYER M4 ;
        RECT  336 296.436 340 296.628 ;
    END
  END m_axil_if_araddr[19]
  PIN m_axil_if_araddr[1]
    DIRECTION OUTPUT ;
    USE SIGNAL ;
    PORT
      LAYER M4 ;
        RECT  336 210.252 340 210.444 ;
    END
  END m_axil_if_araddr[1]
  PIN m_axil_if_araddr[20]
    DIRECTION OUTPUT ;
    USE SIGNAL ;
    PORT
      LAYER M4 ;
        RECT  336 217.434 340 217.626 ;
    END
  END m_axil_if_araddr[20]
  PIN m_axil_if_araddr[21]
    DIRECTION OUTPUT ;
    USE SIGNAL ;
    PORT
      LAYER M4 ;
        RECT  336 232.824 340 233.016 ;
    END
  END m_axil_if_araddr[21]
  PIN m_axil_if_araddr[22]
    DIRECTION OUTPUT ;
    USE SIGNAL ;
    PORT
      LAYER M4 ;
        RECT  336 236.928 340 237.12 ;
    END
  END m_axil_if_araddr[22]
  PIN m_axil_if_araddr[23]
    DIRECTION OUTPUT ;
    USE SIGNAL ;
    PORT
      LAYER M4 ;
        RECT  336 230.772 340 230.964 ;
    END
  END m_axil_if_araddr[23]
  PIN m_axil_if_araddr[24]
    DIRECTION OUTPUT ;
    USE SIGNAL ;
    PORT
      LAYER M4 ;
        RECT  336 253.344 340 253.536 ;
    END
  END m_axil_if_araddr[24]
  PIN m_axil_if_araddr[25]
    DIRECTION OUTPUT ;
    USE SIGNAL ;
    PORT
      LAYER M4 ;
        RECT  336 249.24 340 249.432 ;
    END
  END m_axil_if_araddr[25]
  PIN m_axil_if_araddr[26]
    DIRECTION OUTPUT ;
    USE SIGNAL ;
    PORT
      LAYER M4 ;
        RECT  336 256.422 340 256.614 ;
    END
  END m_axil_if_araddr[26]
  PIN m_axil_if_araddr[27]
    DIRECTION OUTPUT ;
    USE SIGNAL ;
    PORT
      LAYER M4 ;
        RECT  336 229.746 340 229.938 ;
    END
  END m_axil_if_araddr[27]
  PIN m_axil_if_araddr[28]
    DIRECTION OUTPUT ;
    USE SIGNAL ;
    PORT
      LAYER M4 ;
        RECT  336 226.668 340 226.86 ;
    END
  END m_axil_if_araddr[28]
  PIN m_axil_if_araddr[29]
    DIRECTION OUTPUT ;
    USE SIGNAL ;
    PORT
      LAYER M4 ;
        RECT  336 294.384 340 294.576 ;
    END
  END m_axil_if_araddr[29]
  PIN m_axil_if_araddr[2]
    DIRECTION OUTPUT ;
    USE SIGNAL ;
    PORT
      LAYER M4 ;
        RECT  336 300.54 340 300.732 ;
    END
  END m_axil_if_araddr[2]
  PIN m_axil_if_araddr[30]
    DIRECTION OUTPUT ;
    USE SIGNAL ;
    PORT
      LAYER M4 ;
        RECT  336 295.41 340 295.602 ;
    END
  END m_axil_if_araddr[30]
  PIN m_axil_if_araddr[31]
    DIRECTION OUTPUT ;
    USE SIGNAL ;
    PORT
      LAYER M4 ;
        RECT  336 231.798 340 231.99 ;
    END
  END m_axil_if_araddr[31]
  PIN m_axil_if_araddr[3]
    DIRECTION OUTPUT ;
    USE SIGNAL ;
    PORT
      LAYER M4 ;
        RECT  336 250.266 340 250.458 ;
    END
  END m_axil_if_araddr[3]
  PIN m_axil_if_araddr[4]
    DIRECTION OUTPUT ;
    USE SIGNAL ;
    PORT
      LAYER M4 ;
        RECT  336 248.214 340 248.406 ;
    END
  END m_axil_if_araddr[4]
  PIN m_axil_if_araddr[5]
    DIRECTION OUTPUT ;
    USE SIGNAL ;
    PORT
      LAYER M4 ;
        RECT  336 262.578 340 262.77 ;
    END
  END m_axil_if_araddr[5]
  PIN m_axil_if_araddr[6]
    DIRECTION OUTPUT ;
    USE SIGNAL ;
    PORT
      LAYER M4 ;
        RECT  336 281.046 340 281.238 ;
    END
  END m_axil_if_araddr[6]
  PIN m_axil_if_araddr[7]
    DIRECTION OUTPUT ;
    USE SIGNAL ;
    PORT
      LAYER M4 ;
        RECT  336 308.748 340 308.94 ;
    END
  END m_axil_if_araddr[7]
  PIN m_axil_if_araddr[8]
    DIRECTION OUTPUT ;
    USE SIGNAL ;
    PORT
      LAYER M4 ;
        RECT  336 220.512 340 220.704 ;
    END
  END m_axil_if_araddr[8]
  PIN m_axil_if_araddr[9]
    DIRECTION OUTPUT ;
    USE SIGNAL ;
    PORT
      LAYER M4 ;
        RECT  336 215.382 340 215.574 ;
    END
  END m_axil_if_araddr[9]
  PIN m_axil_if_arready
    DIRECTION INPUT ;
    USE SIGNAL ;
    PORT
      LAYER M4 ;
        RECT  336 225.642 340 225.834 ;
    END
  END m_axil_if_arready
  PIN m_axil_if_arvalid
    DIRECTION OUTPUT ;
    USE SIGNAL ;
    PORT
      LAYER M4 ;
        RECT  336 212.304 340 212.496 ;
    END
  END m_axil_if_arvalid
  PIN m_axil_if_rdata[0]
    DIRECTION INPUT ;
    USE SIGNAL ;
    PORT
      LAYER M4 ;
        RECT  336 266.682 340 266.874 ;
    END
  END m_axil_if_rdata[0]
  PIN m_axil_if_rdata[10]
    DIRECTION INPUT ;
    USE SIGNAL ;
    PORT
      LAYER M4 ;
        RECT  336 167.16 340 167.352 ;
    END
  END m_axil_if_rdata[10]
  PIN m_axil_if_rdata[11]
    DIRECTION INPUT ;
    USE SIGNAL ;
    PORT
      LAYER M4 ;
        RECT  336 166.134 340 166.326 ;
    END
  END m_axil_if_rdata[11]
  PIN m_axil_if_rdata[12]
    DIRECTION INPUT ;
    USE SIGNAL ;
    PORT
      LAYER M5 ;
        RECT  5.052 0 5.244 4 ;
    END
  END m_axil_if_rdata[12]
  PIN m_axil_if_rdata[13]
    DIRECTION INPUT ;
    USE SIGNAL ;
    PORT
      LAYER M5 ;
        RECT  6.078 0 6.27 4 ;
    END
  END m_axil_if_rdata[13]
  PIN m_axil_if_rdata[14]
    DIRECTION INPUT ;
    USE SIGNAL ;
    PORT
      LAYER M5 ;
        RECT  7.104 0 7.296 4 ;
    END
  END m_axil_if_rdata[14]
  PIN m_axil_if_rdata[15]
    DIRECTION INPUT ;
    USE SIGNAL ;
    PORT
      LAYER M4 ;
        RECT  336 301.566 340 301.758 ;
    END
  END m_axil_if_rdata[15]
  PIN m_axil_if_rdata[16]
    DIRECTION INPUT ;
    USE SIGNAL ;
    PORT
      LAYER M4 ;
        RECT  336 234.876 340 235.068 ;
    END
  END m_axil_if_rdata[16]
  PIN m_axil_if_rdata[17]
    DIRECTION INPUT ;
    USE SIGNAL ;
    PORT
      LAYER M4 ;
        RECT  336 287.202 340 287.394 ;
    END
  END m_axil_if_rdata[17]
  PIN m_axil_if_rdata[18]
    DIRECTION INPUT ;
    USE SIGNAL ;
    PORT
      LAYER M4 ;
        RECT  336 209.226 340 209.418 ;
    END
  END m_axil_if_rdata[18]
  PIN m_axil_if_rdata[19]
    DIRECTION INPUT ;
    USE SIGNAL ;
    PORT
      LAYER M4 ;
        RECT  336 211.278 340 211.47 ;
    END
  END m_axil_if_rdata[19]
  PIN m_axil_if_rdata[1]
    DIRECTION INPUT ;
    USE SIGNAL ;
    PORT
      LAYER M4 ;
        RECT  336 259.5 340 259.692 ;
    END
  END m_axil_if_rdata[1]
  PIN m_axil_if_rdata[20]
    DIRECTION INPUT ;
    USE SIGNAL ;
    PORT
      LAYER M4 ;
        RECT  336 206.148 340 206.34 ;
    END
  END m_axil_if_rdata[20]
  PIN m_axil_if_rdata[21]
    DIRECTION INPUT ;
    USE SIGNAL ;
    PORT
      LAYER M4 ;
        RECT  336 309.774 340 309.966 ;
    END
  END m_axil_if_rdata[21]
  PIN m_axil_if_rdata[22]
    DIRECTION INPUT ;
    USE SIGNAL ;
    PORT
      LAYER M4 ;
        RECT  336 208.2 340 208.392 ;
    END
  END m_axil_if_rdata[22]
  PIN m_axil_if_rdata[23]
    DIRECTION INPUT ;
    USE SIGNAL ;
    PORT
      LAYER M4 ;
        RECT  336 228.72 340 228.912 ;
    END
  END m_axil_if_rdata[23]
  PIN m_axil_if_rdata[24]
    DIRECTION INPUT ;
    USE SIGNAL ;
    PORT
      LAYER M4 ;
        RECT  336 221.538 340 221.73 ;
    END
  END m_axil_if_rdata[24]
  PIN m_axil_if_rdata[25]
    DIRECTION INPUT ;
    USE SIGNAL ;
    PORT
      LAYER M4 ;
        RECT  336 219.486 340 219.678 ;
    END
  END m_axil_if_rdata[25]
  PIN m_axil_if_rdata[26]
    DIRECTION INPUT ;
    USE SIGNAL ;
    PORT
      LAYER M4 ;
        RECT  336 235.902 340 236.094 ;
    END
  END m_axil_if_rdata[26]
  PIN m_axil_if_rdata[27]
    DIRECTION INPUT ;
    USE SIGNAL ;
    PORT
      LAYER M4 ;
        RECT  336 207.174 340 207.366 ;
    END
  END m_axil_if_rdata[27]
  PIN m_axil_if_rdata[28]
    DIRECTION INPUT ;
    USE SIGNAL ;
    PORT
      LAYER M4 ;
        RECT  336 299.514 340 299.706 ;
    END
  END m_axil_if_rdata[28]
  PIN m_axil_if_rdata[29]
    DIRECTION INPUT ;
    USE SIGNAL ;
    PORT
      LAYER M4 ;
        RECT  336 284.124 340 284.316 ;
    END
  END m_axil_if_rdata[29]
  PIN m_axil_if_rdata[2]
    DIRECTION INPUT ;
    USE SIGNAL ;
    PORT
      LAYER M5 ;
        RECT  249.24 336 249.432 340 ;
    END
  END m_axil_if_rdata[2]
  PIN m_axil_if_rdata[30]
    DIRECTION INPUT ;
    USE SIGNAL ;
    PORT
      LAYER M4 ;
        RECT  336 237.954 340 238.146 ;
    END
  END m_axil_if_rdata[30]
  PIN m_axil_if_rdata[31]
    DIRECTION INPUT ;
    USE SIGNAL ;
    PORT
      LAYER M4 ;
        RECT  336 224.616 340 224.808 ;
    END
  END m_axil_if_rdata[31]
  PIN m_axil_if_rdata[3]
    DIRECTION INPUT ;
    USE SIGNAL ;
    PORT
      LAYER M5 ;
        RECT  247.188 336 247.38 340 ;
    END
  END m_axil_if_rdata[3]
  PIN m_axil_if_rdata[4]
    DIRECTION INPUT ;
    USE SIGNAL ;
    PORT
      LAYER M5 ;
        RECT  234.876 336 235.068 340 ;
    END
  END m_axil_if_rdata[4]
  PIN m_axil_if_rdata[5]
    DIRECTION INPUT ;
    USE SIGNAL ;
    PORT
      LAYER M4 ;
        RECT  336 286.176 340 286.368 ;
    END
  END m_axil_if_rdata[5]
  PIN m_axil_if_rdata[6]
    DIRECTION INPUT ;
    USE SIGNAL ;
    PORT
      LAYER M4 ;
        RECT  336 242.058 340 242.25 ;
    END
  END m_axil_if_rdata[6]
  PIN m_axil_if_rdata[7]
    DIRECTION INPUT ;
    USE SIGNAL ;
    PORT
      LAYER M4 ;
        RECT  336 168.186 340 168.378 ;
    END
  END m_axil_if_rdata[7]
  PIN m_axil_if_rdata[8]
    DIRECTION INPUT ;
    USE SIGNAL ;
    PORT
      LAYER M4 ;
        RECT  336 240.006 340 240.198 ;
    END
  END m_axil_if_rdata[8]
  PIN m_axil_if_rdata[9]
    DIRECTION INPUT ;
    USE SIGNAL ;
    PORT
      LAYER M4 ;
        RECT  336 165.108 340 165.3 ;
    END
  END m_axil_if_rdata[9]
  PIN m_axil_if_rready
    DIRECTION OUTPUT ;
    USE SIGNAL ;
    PORT
      LAYER M5 ;
        RECT  189.732 336 189.924 340 ;
    END
  END m_axil_if_rready
  PIN m_axil_if_rresp[0]
    DIRECTION INPUT ;
    USE SIGNAL ;
    PORT
      LAYER M5 ;
        RECT  8.13 0 8.322 4 ;
    END
  END m_axil_if_rresp[0]
  PIN m_axil_if_rresp[1]
    DIRECTION INPUT ;
    USE SIGNAL ;
    PORT
      LAYER M5 ;
        RECT  9.156 0 9.348 4 ;
    END
  END m_axil_if_rresp[1]
  PIN m_axil_if_rvalid
    DIRECTION INPUT ;
    USE SIGNAL ;
    PORT
      LAYER M4 ;
        RECT  336 265.656 340 265.848 ;
    END
  END m_axil_if_rvalid
  PIN rst_n
    DIRECTION INPUT ;
    USE SIGNAL ;
    PORT
      LAYER M4 ;
        RECT  336 11.208 340 11.4 ;
    END
  END rst_n
  PIN s_axil_araddr[0]
    DIRECTION INPUT ;
    USE SIGNAL ;
    PORT
      LAYER M5 ;
        RECT  71.742 0 71.934 4 ;
    END
  END s_axil_araddr[0]
  PIN s_axil_araddr[10]
    DIRECTION INPUT ;
    USE SIGNAL ;
    PORT
      LAYER M5 ;
        RECT  107.652 0 107.844 4 ;
    END
  END s_axil_araddr[10]
  PIN s_axil_araddr[11]
    DIRECTION INPUT ;
    USE SIGNAL ;
    PORT
      LAYER M5 ;
        RECT  86.106 0 86.298 4 ;
    END
  END s_axil_araddr[11]
  PIN s_axil_araddr[1]
    DIRECTION INPUT ;
    USE SIGNAL ;
    PORT
      LAYER M5 ;
        RECT  85.08 0 85.272 4 ;
    END
  END s_axil_araddr[1]
  PIN s_axil_araddr[2]
    DIRECTION INPUT ;
    USE SIGNAL ;
    PORT
      LAYER M5 ;
        RECT  82.002 0 82.194 4 ;
    END
  END s_axil_araddr[2]
  PIN s_axil_araddr[3]
    DIRECTION INPUT ;
    USE SIGNAL ;
    PORT
      LAYER M5 ;
        RECT  87.132 0 87.324 4 ;
    END
  END s_axil_araddr[3]
  PIN s_axil_araddr[4]
    DIRECTION INPUT ;
    USE SIGNAL ;
    PORT
      LAYER M5 ;
        RECT  84.054 0 84.246 4 ;
    END
  END s_axil_araddr[4]
  PIN s_axil_araddr[5]
    DIRECTION INPUT ;
    USE SIGNAL ;
    PORT
      LAYER M5 ;
        RECT  83.028 0 83.22 4 ;
    END
  END s_axil_araddr[5]
  PIN s_axil_araddr[6]
    DIRECTION INPUT ;
    USE SIGNAL ;
    PORT
      LAYER M5 ;
        RECT  90.21 0 90.402 4 ;
    END
  END s_axil_araddr[6]
  PIN s_axil_araddr[7]
    DIRECTION INPUT ;
    USE SIGNAL ;
    PORT
      LAYER M5 ;
        RECT  105.6 0 105.792 4 ;
    END
  END s_axil_araddr[7]
  PIN s_axil_araddr[8]
    DIRECTION INPUT ;
    USE SIGNAL ;
    PORT
      LAYER M5 ;
        RECT  104.574 0 104.766 4 ;
    END
  END s_axil_araddr[8]
  PIN s_axil_araddr[9]
    DIRECTION INPUT ;
    USE SIGNAL ;
    PORT
      LAYER M5 ;
        RECT  88.158 0 88.35 4 ;
    END
  END s_axil_araddr[9]
  PIN s_axil_arready
    DIRECTION OUTPUT ;
    USE SIGNAL ;
    PORT
      LAYER M5 ;
        RECT  106.626 0 106.818 4 ;
    END
  END s_axil_arready
  PIN s_axil_arvalid
    DIRECTION INPUT ;
    USE SIGNAL ;
    PORT
      LAYER M5 ;
        RECT  89.184 0 89.376 4 ;
    END
  END s_axil_arvalid
  PIN s_axil_awaddr[0]
    DIRECTION INPUT ;
    USE SIGNAL ;
    PORT
      LAYER M5 ;
        RECT  173.316 0 173.508 4 ;
    END
  END s_axil_awaddr[0]
  PIN s_axil_awaddr[10]
    DIRECTION INPUT ;
    USE SIGNAL ;
    PORT
      LAYER M5 ;
        RECT  162.03 0 162.222 4 ;
    END
  END s_axil_awaddr[10]
  PIN s_axil_awaddr[11]
    DIRECTION INPUT ;
    USE SIGNAL ;
    PORT
      LAYER M5 ;
        RECT  145.614 0 145.806 4 ;
    END
  END s_axil_awaddr[11]
  PIN s_axil_awaddr[1]
    DIRECTION INPUT ;
    USE SIGNAL ;
    PORT
      LAYER M5 ;
        RECT  166.134 0 166.326 4 ;
    END
  END s_axil_awaddr[1]
  PIN s_axil_awaddr[2]
    DIRECTION INPUT ;
    USE SIGNAL ;
    PORT
      LAYER M5 ;
        RECT  150.744 0 150.936 4 ;
    END
  END s_axil_awaddr[2]
  PIN s_axil_awaddr[3]
    DIRECTION INPUT ;
    USE SIGNAL ;
    PORT
      LAYER M5 ;
        RECT  158.952 0 159.144 4 ;
    END
  END s_axil_awaddr[3]
  PIN s_axil_awaddr[4]
    DIRECTION INPUT ;
    USE SIGNAL ;
    PORT
      LAYER M5 ;
        RECT  140.484 0 140.676 4 ;
    END
  END s_axil_awaddr[4]
  PIN s_axil_awaddr[5]
    DIRECTION INPUT ;
    USE SIGNAL ;
    PORT
      LAYER M5 ;
        RECT  168.186 0 168.378 4 ;
    END
  END s_axil_awaddr[5]
  PIN s_axil_awaddr[6]
    DIRECTION INPUT ;
    USE SIGNAL ;
    PORT
      LAYER M5 ;
        RECT  143.562 0 143.754 4 ;
    END
  END s_axil_awaddr[6]
  PIN s_axil_awaddr[7]
    DIRECTION INPUT ;
    USE SIGNAL ;
    PORT
      LAYER M5 ;
        RECT  139.458 0 139.65 4 ;
    END
  END s_axil_awaddr[7]
  PIN s_axil_awaddr[8]
    DIRECTION INPUT ;
    USE SIGNAL ;
    PORT
      LAYER M5 ;
        RECT  141.51 0 141.702 4 ;
    END
  END s_axil_awaddr[8]
  PIN s_axil_awaddr[9]
    DIRECTION INPUT ;
    USE SIGNAL ;
    PORT
      LAYER M5 ;
        RECT  154.848 0 155.04 4 ;
    END
  END s_axil_awaddr[9]
  PIN s_axil_awready
    DIRECTION OUTPUT ;
    USE SIGNAL ;
    PORT
      LAYER M5 ;
        RECT  159.978 0 160.17 4 ;
    END
  END s_axil_awready
  PIN s_axil_awvalid
    DIRECTION INPUT ;
    USE SIGNAL ;
    PORT
      LAYER M5 ;
        RECT  138.432 0 138.624 4 ;
    END
  END s_axil_awvalid
  PIN s_axil_bready
    DIRECTION INPUT ;
    USE SIGNAL ;
    PORT
      LAYER M5 ;
        RECT  148.692 0 148.884 4 ;
    END
  END s_axil_bready
  PIN s_axil_bresp[0]
    DIRECTION OUTPUT ;
    USE SIGNAL ;
    PORT
      LAYER M5 ;
        RECT  29.676 336 29.868 340 ;
    END
  END s_axil_bresp[0]
  PIN s_axil_bresp[1]
    DIRECTION OUTPUT ;
    USE SIGNAL ;
    PORT
      LAYER M4 ;
        RECT  0 290.28 4 290.472 ;
    END
  END s_axil_bresp[1]
  PIN s_axil_bvalid
    DIRECTION OUTPUT ;
    USE SIGNAL ;
    PORT
      LAYER M5 ;
        RECT  161.004 0 161.196 4 ;
    END
  END s_axil_bvalid
  PIN s_axil_rdata[0]
    DIRECTION OUTPUT ;
    USE SIGNAL ;
    PORT
      LAYER M5 ;
        RECT  115.86 0 116.052 4 ;
    END
  END s_axil_rdata[0]
  PIN s_axil_rdata[10]
    DIRECTION OUTPUT ;
    USE SIGNAL ;
    PORT
      LAYER M5 ;
        RECT  120.99 0 121.182 4 ;
    END
  END s_axil_rdata[10]
  PIN s_axil_rdata[11]
    DIRECTION OUTPUT ;
    USE SIGNAL ;
    PORT
      LAYER M5 ;
        RECT  119.964 0 120.156 4 ;
    END
  END s_axil_rdata[11]
  PIN s_axil_rdata[12]
    DIRECTION OUTPUT ;
    USE SIGNAL ;
    PORT
      LAYER M5 ;
        RECT  118.938 0 119.13 4 ;
    END
  END s_axil_rdata[12]
  PIN s_axil_rdata[13]
    DIRECTION OUTPUT ;
    USE SIGNAL ;
    PORT
      LAYER M5 ;
        RECT  117.912 0 118.104 4 ;
    END
  END s_axil_rdata[13]
  PIN s_axil_rdata[14]
    DIRECTION OUTPUT ;
    USE SIGNAL ;
    PORT
      LAYER M5 ;
        RECT  74.82 0 75.012 4 ;
    END
  END s_axil_rdata[14]
  PIN s_axil_rdata[15]
    DIRECTION OUTPUT ;
    USE SIGNAL ;
    PORT
      LAYER M5 ;
        RECT  122.016 0 122.208 4 ;
    END
  END s_axil_rdata[15]
  PIN s_axil_rdata[16]
    DIRECTION OUTPUT ;
    USE SIGNAL ;
    PORT
      LAYER M5 ;
        RECT  124.068 0 124.26 4 ;
    END
  END s_axil_rdata[16]
  PIN s_axil_rdata[17]
    DIRECTION OUTPUT ;
    USE SIGNAL ;
    PORT
      LAYER M5 ;
        RECT  126.12 0 126.312 4 ;
    END
  END s_axil_rdata[17]
  PIN s_axil_rdata[18]
    DIRECTION OUTPUT ;
    USE SIGNAL ;
    PORT
      LAYER M5 ;
        RECT  123.042 0 123.234 4 ;
    END
  END s_axil_rdata[18]
  PIN s_axil_rdata[19]
    DIRECTION OUTPUT ;
    USE SIGNAL ;
    PORT
      LAYER M5 ;
        RECT  125.094 0 125.286 4 ;
    END
  END s_axil_rdata[19]
  PIN s_axil_rdata[1]
    DIRECTION OUTPUT ;
    USE SIGNAL ;
    PORT
      LAYER M5 ;
        RECT  76.872 0 77.064 4 ;
    END
  END s_axil_rdata[1]
  PIN s_axil_rdata[20]
    DIRECTION OUTPUT ;
    USE SIGNAL ;
    PORT
      LAYER M5 ;
        RECT  128.172 0 128.364 4 ;
    END
  END s_axil_rdata[20]
  PIN s_axil_rdata[21]
    DIRECTION OUTPUT ;
    USE SIGNAL ;
    PORT
      LAYER M5 ;
        RECT  136.38 0 136.572 4 ;
    END
  END s_axil_rdata[21]
  PIN s_axil_rdata[22]
    DIRECTION OUTPUT ;
    USE SIGNAL ;
    PORT
      LAYER M5 ;
        RECT  130.224 0 130.416 4 ;
    END
  END s_axil_rdata[22]
  PIN s_axil_rdata[23]
    DIRECTION OUTPUT ;
    USE SIGNAL ;
    PORT
      LAYER M5 ;
        RECT  127.146 0 127.338 4 ;
    END
  END s_axil_rdata[23]
  PIN s_axil_rdata[24]
    DIRECTION OUTPUT ;
    USE SIGNAL ;
    PORT
      LAYER M5 ;
        RECT  155.874 0 156.066 4 ;
    END
  END s_axil_rdata[24]
  PIN s_axil_rdata[25]
    DIRECTION OUTPUT ;
    USE SIGNAL ;
    PORT
      LAYER M5 ;
        RECT  131.25 0 131.442 4 ;
    END
  END s_axil_rdata[25]
  PIN s_axil_rdata[26]
    DIRECTION OUTPUT ;
    USE SIGNAL ;
    PORT
      LAYER M5 ;
        RECT  133.302 0 133.494 4 ;
    END
  END s_axil_rdata[26]
  PIN s_axil_rdata[27]
    DIRECTION OUTPUT ;
    USE SIGNAL ;
    PORT
      LAYER M5 ;
        RECT  135.354 0 135.546 4 ;
    END
  END s_axil_rdata[27]
  PIN s_axil_rdata[28]
    DIRECTION OUTPUT ;
    USE SIGNAL ;
    PORT
      LAYER M5 ;
        RECT  152.796 0 152.988 4 ;
    END
  END s_axil_rdata[28]
  PIN s_axil_rdata[29]
    DIRECTION OUTPUT ;
    USE SIGNAL ;
    PORT
      LAYER M5 ;
        RECT  129.198 0 129.39 4 ;
    END
  END s_axil_rdata[29]
  PIN s_axil_rdata[2]
    DIRECTION OUTPUT ;
    USE SIGNAL ;
    PORT
      LAYER M5 ;
        RECT  114.834 0 115.026 4 ;
    END
  END s_axil_rdata[2]
  PIN s_axil_rdata[30]
    DIRECTION OUTPUT ;
    USE SIGNAL ;
    PORT
      LAYER M5 ;
        RECT  134.328 0 134.52 4 ;
    END
  END s_axil_rdata[30]
  PIN s_axil_rdata[31]
    DIRECTION OUTPUT ;
    USE SIGNAL ;
    PORT
      LAYER M5 ;
        RECT  132.276 0 132.468 4 ;
    END
  END s_axil_rdata[31]
  PIN s_axil_rdata[3]
    DIRECTION OUTPUT ;
    USE SIGNAL ;
    PORT
      LAYER M5 ;
        RECT  79.95 0 80.142 4 ;
    END
  END s_axil_rdata[3]
  PIN s_axil_rdata[4]
    DIRECTION OUTPUT ;
    USE SIGNAL ;
    PORT
      LAYER M5 ;
        RECT  77.898 0 78.09 4 ;
    END
  END s_axil_rdata[4]
  PIN s_axil_rdata[5]
    DIRECTION OUTPUT ;
    USE SIGNAL ;
    PORT
      LAYER M5 ;
        RECT  113.808 0 114 4 ;
    END
  END s_axil_rdata[5]
  PIN s_axil_rdata[6]
    DIRECTION OUTPUT ;
    USE SIGNAL ;
    PORT
      LAYER M5 ;
        RECT  111.756 0 111.948 4 ;
    END
  END s_axil_rdata[6]
  PIN s_axil_rdata[7]
    DIRECTION OUTPUT ;
    USE SIGNAL ;
    PORT
      LAYER M5 ;
        RECT  80.976 0 81.168 4 ;
    END
  END s_axil_rdata[7]
  PIN s_axil_rdata[8]
    DIRECTION OUTPUT ;
    USE SIGNAL ;
    PORT
      LAYER M5 ;
        RECT  110.73 0 110.922 4 ;
    END
  END s_axil_rdata[8]
  PIN s_axil_rdata[9]
    DIRECTION OUTPUT ;
    USE SIGNAL ;
    PORT
      LAYER M5 ;
        RECT  78.924 0 79.116 4 ;
    END
  END s_axil_rdata[9]
  PIN s_axil_rready
    DIRECTION INPUT ;
    USE SIGNAL ;
    PORT
      LAYER M5 ;
        RECT  93.288 0 93.48 4 ;
    END
  END s_axil_rready
  PIN s_axil_rresp[0]
    DIRECTION OUTPUT ;
    USE SIGNAL ;
    PORT
      LAYER M5 ;
        RECT  43.014 336 43.206 340 ;
    END
  END s_axil_rresp[0]
  PIN s_axil_rresp[1]
    DIRECTION OUTPUT ;
    USE SIGNAL ;
    PORT
      LAYER M5 ;
        RECT  73.794 0 73.986 4 ;
    END
  END s_axil_rresp[1]
  PIN s_axil_rvalid
    DIRECTION OUTPUT ;
    USE SIGNAL ;
    PORT
      LAYER M5 ;
        RECT  92.262 0 92.454 4 ;
    END
  END s_axil_rvalid
  PIN s_axil_wdata[0]
    DIRECTION INPUT ;
    USE SIGNAL ;
    PORT
      LAYER M5 ;
        RECT  94.314 0 94.506 4 ;
    END
  END s_axil_wdata[0]
  PIN s_axil_wdata[10]
    DIRECTION INPUT ;
    USE SIGNAL ;
    PORT
      LAYER M5 ;
        RECT  112.782 0 112.974 4 ;
    END
  END s_axil_wdata[10]
  PIN s_axil_wdata[11]
    DIRECTION INPUT ;
    USE SIGNAL ;
    PORT
      LAYER M5 ;
        RECT  75.846 0 76.038 4 ;
    END
  END s_axil_wdata[11]
  PIN s_axil_wdata[12]
    DIRECTION INPUT ;
    USE SIGNAL ;
    PORT
      LAYER M5 ;
        RECT  91.236 0 91.428 4 ;
    END
  END s_axil_wdata[12]
  PIN s_axil_wdata[13]
    DIRECTION INPUT ;
    USE SIGNAL ;
    PORT
      LAYER M5 ;
        RECT  109.704 0 109.896 4 ;
    END
  END s_axil_wdata[13]
  PIN s_axil_wdata[14]
    DIRECTION INPUT ;
    USE SIGNAL ;
    PORT
      LAYER M5 ;
        RECT  108.678 0 108.87 4 ;
    END
  END s_axil_wdata[14]
  PIN s_axil_wdata[15]
    DIRECTION INPUT ;
    USE SIGNAL ;
    PORT
      LAYER M5 ;
        RECT  72.768 0 72.96 4 ;
    END
  END s_axil_wdata[15]
  PIN s_axil_wdata[16]
    DIRECTION INPUT ;
    USE SIGNAL ;
    PORT
      LAYER M5 ;
        RECT  151.77 0 151.962 4 ;
    END
  END s_axil_wdata[16]
  PIN s_axil_wdata[17]
    DIRECTION INPUT ;
    USE SIGNAL ;
    PORT
      LAYER M5 ;
        RECT  172.29 0 172.482 4 ;
    END
  END s_axil_wdata[17]
  PIN s_axil_wdata[18]
    DIRECTION INPUT ;
    USE SIGNAL ;
    PORT
      LAYER M5 ;
        RECT  164.082 0 164.274 4 ;
    END
  END s_axil_wdata[18]
  PIN s_axil_wdata[19]
    DIRECTION INPUT ;
    USE SIGNAL ;
    PORT
      LAYER M5 ;
        RECT  153.822 0 154.014 4 ;
    END
  END s_axil_wdata[19]
  PIN s_axil_wdata[1]
    DIRECTION INPUT ;
    USE SIGNAL ;
    PORT
      LAYER M5 ;
        RECT  97.392 0 97.584 4 ;
    END
  END s_axil_wdata[1]
  PIN s_axil_wdata[20]
    DIRECTION INPUT ;
    USE SIGNAL ;
    PORT
      LAYER M5 ;
        RECT  165.108 0 165.3 4 ;
    END
  END s_axil_wdata[20]
  PIN s_axil_wdata[21]
    DIRECTION INPUT ;
    USE SIGNAL ;
    PORT
      LAYER M5 ;
        RECT  170.238 0 170.43 4 ;
    END
  END s_axil_wdata[21]
  PIN s_axil_wdata[22]
    DIRECTION INPUT ;
    USE SIGNAL ;
    PORT
      LAYER M5 ;
        RECT  147.666 0 147.858 4 ;
    END
  END s_axil_wdata[22]
  PIN s_axil_wdata[23]
    DIRECTION INPUT ;
    USE SIGNAL ;
    PORT
      LAYER M5 ;
        RECT  137.406 0 137.598 4 ;
    END
  END s_axil_wdata[23]
  PIN s_axil_wdata[24]
    DIRECTION INPUT ;
    USE SIGNAL ;
    PORT
      LAYER M5 ;
        RECT  171.264 0 171.456 4 ;
    END
  END s_axil_wdata[24]
  PIN s_axil_wdata[25]
    DIRECTION INPUT ;
    USE SIGNAL ;
    PORT
      LAYER M5 ;
        RECT  144.588 0 144.78 4 ;
    END
  END s_axil_wdata[25]
  PIN s_axil_wdata[26]
    DIRECTION INPUT ;
    USE SIGNAL ;
    PORT
      LAYER M5 ;
        RECT  142.536 0 142.728 4 ;
    END
  END s_axil_wdata[26]
  PIN s_axil_wdata[27]
    DIRECTION INPUT ;
    USE SIGNAL ;
    PORT
      LAYER M5 ;
        RECT  163.056 0 163.248 4 ;
    END
  END s_axil_wdata[27]
  PIN s_axil_wdata[28]
    DIRECTION INPUT ;
    USE SIGNAL ;
    PORT
      LAYER M5 ;
        RECT  167.16 0 167.352 4 ;
    END
  END s_axil_wdata[28]
  PIN s_axil_wdata[29]
    DIRECTION INPUT ;
    USE SIGNAL ;
    PORT
      LAYER M5 ;
        RECT  146.64 0 146.832 4 ;
    END
  END s_axil_wdata[29]
  PIN s_axil_wdata[2]
    DIRECTION INPUT ;
    USE SIGNAL ;
    PORT
      LAYER M5 ;
        RECT  98.418 0 98.61 4 ;
    END
  END s_axil_wdata[2]
  PIN s_axil_wdata[30]
    DIRECTION INPUT ;
    USE SIGNAL ;
    PORT
      LAYER M5 ;
        RECT  149.718 0 149.91 4 ;
    END
  END s_axil_wdata[30]
  PIN s_axil_wdata[31]
    DIRECTION INPUT ;
    USE SIGNAL ;
    PORT
      LAYER M5 ;
        RECT  157.926 0 158.118 4 ;
    END
  END s_axil_wdata[31]
  PIN s_axil_wdata[3]
    DIRECTION INPUT ;
    USE SIGNAL ;
    PORT
      LAYER M5 ;
        RECT  95.34 0 95.532 4 ;
    END
  END s_axil_wdata[3]
  PIN s_axil_wdata[4]
    DIRECTION INPUT ;
    USE SIGNAL ;
    PORT
      LAYER M5 ;
        RECT  99.444 0 99.636 4 ;
    END
  END s_axil_wdata[4]
  PIN s_axil_wdata[5]
    DIRECTION INPUT ;
    USE SIGNAL ;
    PORT
      LAYER M5 ;
        RECT  100.47 0 100.662 4 ;
    END
  END s_axil_wdata[5]
  PIN s_axil_wdata[6]
    DIRECTION INPUT ;
    USE SIGNAL ;
    PORT
      LAYER M5 ;
        RECT  96.366 0 96.558 4 ;
    END
  END s_axil_wdata[6]
  PIN s_axil_wdata[7]
    DIRECTION INPUT ;
    USE SIGNAL ;
    PORT
      LAYER M5 ;
        RECT  101.496 0 101.688 4 ;
    END
  END s_axil_wdata[7]
  PIN s_axil_wdata[8]
    DIRECTION INPUT ;
    USE SIGNAL ;
    PORT
      LAYER M5 ;
        RECT  102.522 0 102.714 4 ;
    END
  END s_axil_wdata[8]
  PIN s_axil_wdata[9]
    DIRECTION INPUT ;
    USE SIGNAL ;
    PORT
      LAYER M5 ;
        RECT  103.548 0 103.74 4 ;
    END
  END s_axil_wdata[9]
  PIN s_axil_wready
    DIRECTION OUTPUT ;
    USE SIGNAL ;
    PORT
      LAYER M5 ;
        RECT  156.9 0 157.092 4 ;
    END
  END s_axil_wready
  PIN s_axil_wstrb[0]
    DIRECTION INPUT ;
    USE SIGNAL ;
    PORT
      LAYER M5 ;
        RECT  10.182 0 10.374 4 ;
    END
  END s_axil_wstrb[0]
  PIN s_axil_wstrb[1]
    DIRECTION INPUT ;
    USE SIGNAL ;
    PORT
      LAYER M5 ;
        RECT  11.208 0 11.4 4 ;
    END
  END s_axil_wstrb[1]
  PIN s_axil_wstrb[2]
    DIRECTION INPUT ;
    USE SIGNAL ;
    PORT
      LAYER M5 ;
        RECT  12.234 0 12.426 4 ;
    END
  END s_axil_wstrb[2]
  PIN s_axil_wstrb[3]
    DIRECTION INPUT ;
    USE SIGNAL ;
    PORT
      LAYER M5 ;
        RECT  13.26 0 13.452 4 ;
    END
  END s_axil_wstrb[3]
  PIN s_axil_wvalid
    DIRECTION INPUT ;
    USE SIGNAL ;
    PORT
      LAYER M5 ;
        RECT  169.212 0 169.404 4 ;
    END
  END s_axil_wvalid
  OBS
    LAYER M1 ;
     RECT  0 0 340 340 ;
    LAYER M2 ;
     RECT  0 0 340 340 ;
    LAYER M3 ;
     RECT  0 0 340 340 ;
    LAYER M4 ;
     RECT  0 0 340 340 ;
  END
END gpu_top
END LIBRARY
